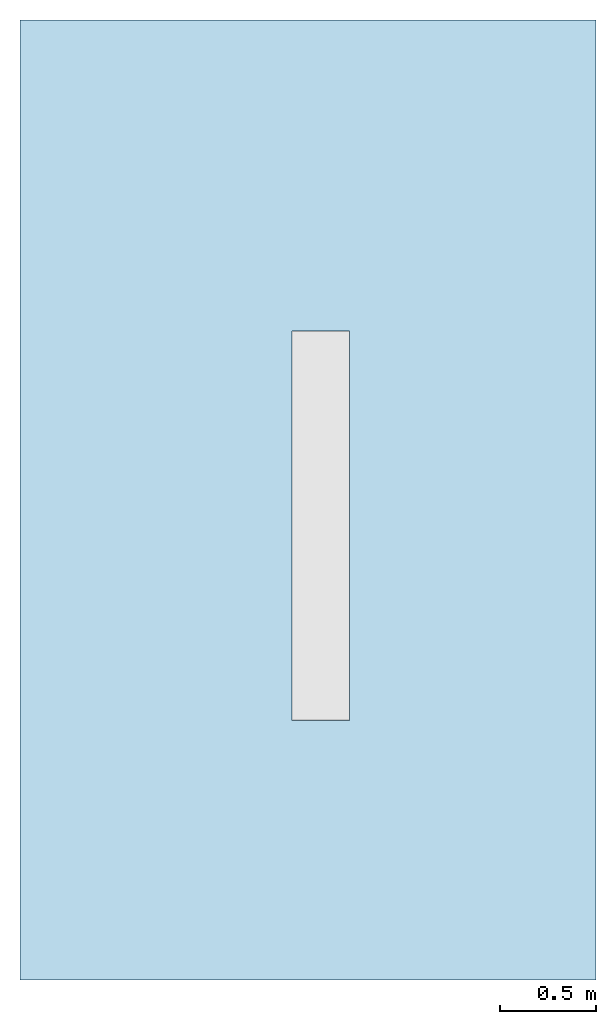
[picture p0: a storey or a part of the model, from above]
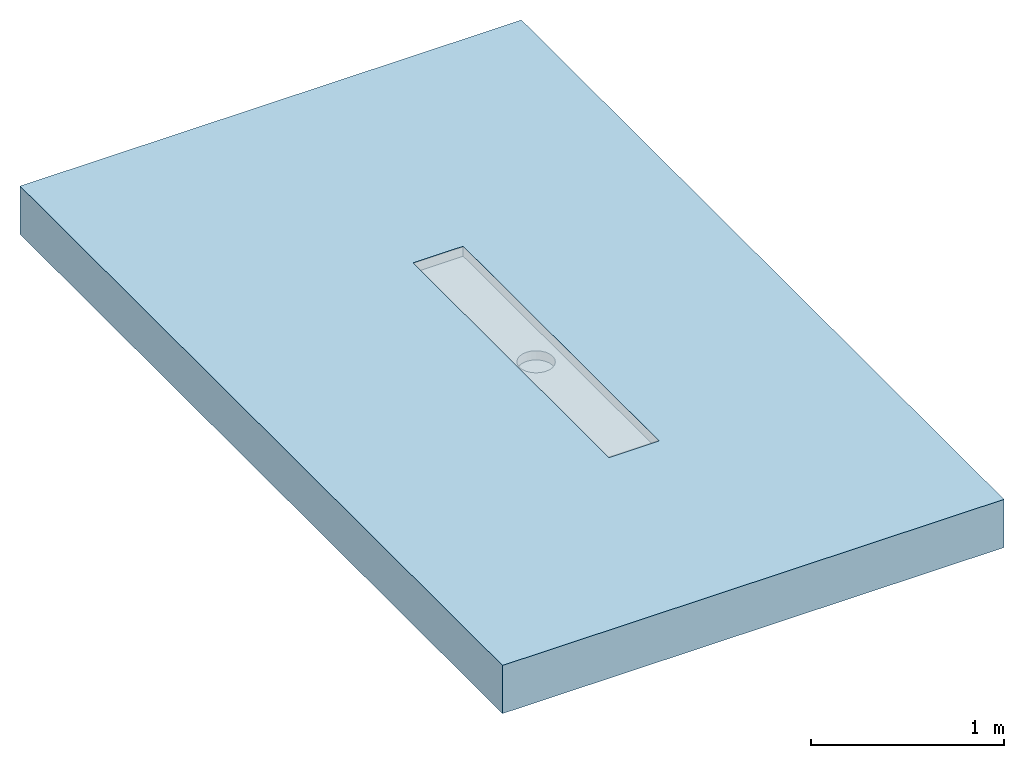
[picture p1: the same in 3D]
Properties of the parts of a building model (IFC2X3)

# File
Description: ViewDefinition [CoordinationView]
File name: Project Number
Time: 2016-11-22T11:03:20
Written by: The EXPRESS Data Manager Version 5.01.0100.02.64mod : 6 Jun 2012
Made in: 20130308_1515(x64) - Exporter 2014.0.2013.0308 - Default UI
Comment: STEP Physical File produced by: The EXPRESS Data Manager Version 5.01.0100.02.64mod : 6 Jun 2012 * Module: EDMstepFileFactory/EDMstandAlone * Creation date: Tue Nov 22 11:03:20 2016 * Host: IN-BLR-PC-0012 * Database: C:\Users\pakumar\AppData\Local\Temp\{40277E8B-09DD-453D-B419-486A75BF092F}\ifc * Database version: 5507 * Database creation date: Tue Nov 22 11:03:19 2016 * Schema: IFC2X3 * Model: DataRepository.ifc * Model creation date: Tue Nov 22 11:03:19 2016 * Header model: DataRepository.ifc_HeaderModel * Header model creation date: Tue Nov 22 11:03:19 2016 * EDMuser: sdai-user * EDMgroup: sdai-group * License ID and type: 5605 : Permanent license. Expiry date: * EDMstepFileFactory options: 020000

# IfcProject, Project Number
LongName: Project Name; Phase: Project Status

# IfcSite, Default
RefLatitude: 42, 21, 30, 344238; RefLongitude: -71, -3, -35, -194702; RefElevation: 0 mm

# IfcBuilding
Pset_BuildingCommon - NumberOfStoreys: 1
Other - Project Status: Project Status; Client Name: Owner; Project Issue Date: Issue Date; Project Address: Enter address here; Project Number: Project Number; Project Name: Project Name

# IfcBuildingStorey, Level 1
LongName: Level 1; Elevation: 0 mm
Constraints - Elevation Base: Project Base Point; Elevation: 0 mm
Graphics - Symbol at End 2 Default: yes; Symbol: Level Head - Circle: Level Head - Circle; Line Weight: 1; Line Pattern: Grid Line 1/2"; Symbol at End 1 Default: no; Color: 0
Identity Data - Name: Level 1; Building Story: yes; Structural: no
Dimensions - Computation Height: 0 mm

# IfcFlowTerminal: 416625 - Hygienic Standard Channel - with Gully 218 - 2000mm LG - 300mm Wide, ACO Tray Channel - Hygienic - Standard - 300mm Wide:416625 - Hygienic Standard Channel - with Gully 218 - 2000mm LG - 300mm Wide:634635
In: Level 1
Material: Stainless Steel AISI 304, Stainless Steel AISI 304 - Grating
Construction - Detail - Outlet 200: yes; Detail - Outlet 142mm: no; Grating: yes; 416864 - 268 x 298mm - Mesh Grating - L15 - Stainless Steel 1.4301: no; 416818 - 268 x 499mm - Ladder Grating - M125 - Stainless Steel 1.4301: no; 416812 - 268 x 298mm - Ladder Grating - R50 - Stainless Steel 1.4301: no; 416945 - 268 x 499mm - Casted Grating - M125 - Stainless Steel 1.4301: no; 416886 - 268 x 499mm - Mesh Grating - L15 - Stainless Steel 1.4301: no; 416814 - 268 x 499mm - Ladder Grating - R50 - Stainless Steel 1.4301: no; 416816 - 268 x 298mm - Ladder Grating - M125 - Stainless Steel 1.4301: no; 416884 - 268 x 298mm - Mesh Grating - L15 - Stainless Steel 1.4301: no; 416866 - 268 x 499mm - Mesh Grating - L15 - Stainless Steel 1.4301: no; 416946 - 268 x 299mm - Casted Grating - M125 - Stainless Steel 1.4301: yes
Mechanical - System Classification: Sanitary
Constraints - Level: Level: Level 1
Identity Data - Mark: 55; Website: www.acobd.com; Watermarked With: BIM Manager Premium Suite.; Watermark1: This file is the property of ACO Technologies PLC.; Watermark2: This file is water marked and users are prohibited to reproduce, adapt, distribute this information.; E-mail Sales: abdcommercial@aco.co.uk; Fax: +44 (0)1462 851490; Watermarked By: www.acobd.com; Manufacturer: ACO Building Drainage; E-mail Technical: abdtechnical@aco.co.uk; Telephone: +44 (0)1462 816666; Address: ACO Business Centre, Caxton Road, Bedford, MK41 0LF; Cost: 0
Phasing - Phase Created: New Construction
Pset_ManufacturerTypeInformation - Manufacturer: ACO Building Drainage
General - Foul air trap seal Colour: Black; Foul air trap Recycled material content: 0%; Channel Recyclable: Fully recyclable; Product Description: ACO Hygiene First Standard Kitchen Tray Channel 300 x 2030 / 200 Dia Outlet & Foul Air Trap; Maintenance guidelines: http://issuu.com/acobuildingdrainage/docs/aco_hygiene_first_catalogue/17?e=0; Channel Dimension: 300 x 2030; Foul air trap Recyclable: Fully recyclable; Product Standard: EN 1253 / EN 1672 / EN ISO 14159; Installation guidelines: http://issuu.com/acobuildingdrainage/docs/aco_hygiene_first_catalogue/17?e=0; Foul air trap seal Material: NBR; Price: POA - contact ACO; Channel Material: Stainless steel 1.4301 (EN 10088); Channel Recycled material content: 20 - 30 %; Outlet Diameter (mm): 200; Product Type: Standard Kitchen Tray Channel; Product Code: 416625; Weight (Kg): 10.7; Product Range: ACO Hygiene First; Load Class: A15 - C250 (EN 1253); Channel Colour: passivated stainless steel surface ( matt grey)
Model Properties - Grating Product Code 416866: Load Class L 15 (EN 1253) - Mesh Grate - Stainless steel 1.4301 (EN 10088) - 268 x 499 - 3.4kg; Grating Product Code 416816: N/A; Grating Product Code 416818: Load Class M 125 (EN 1253) - Ladder Grate - Stainless steel 1.4301 (EN 10088) - 268 x 499 - 6.8kg; Grating Product Code 416864: N/A; Grating Product Code 416886: Load Class L 15 (EN 1253) - Mesh Grate - Stainless steel 1.4301 (EN 10088) - 268 x 499 - 3.5kg; Grating Product Code 416945: Load Class M 125 (EN 1253) - Cast Grate - Stainless steel 1.4301 (EN 10088) - 268 x 499 - 9kg; Grating Product Code 416814: Load Class R 50 (EN 1253) - Ladder Grate - Stainless steel 1.4301 (EN 10088) - 268 x 499 - 4.2kg; Grating Product Code 416812: N/A; Grating Product Code 416946: N/A; Grating Product Code 416884: N/A
Other - Flow: 0.155385 m3/s; 416618 - Hygienic Standard Channel - 2000mm LG - 300mm Wide: yes; Number mesh: 82; 416615 - Hygienic Standard Channel - 600mm LG - 300mm Wide: no; Spigot Outlets Channels: yes; Invert Depth Detail: 51.5 mm; 416614 - Hygienic Standard Channel - 300mm LG - 300mm Wide: no; 416617 - Hygienic Standard Channel - 1500mm LG - 300mm Wide: no; 416616 - Hygienic Standard Channel - 1000mm LG - 300mm Wide: no; 416620 - Hygienic Standard Channel - 4000mm LG - 300mm Wide: no; 416619 - Hygienic Standard Channel - 3000mm LG - 300mm Wide: no
Dimensions - End Plate: 2000 mm; Number of gratings: 4; Grating Void Cut Length: 500 mm; Grating Length: 499 mm; End Connection Plate End: -2000 mm; Floor Cut Void Height: 62.8 mm; Inside Outlet Rad: 98 mm; Endplate Position: 2000 mm; Invert Depth: 50 mm; Grating Height: 21 mm; Outside Outlet Rad: 100 mm; End Connection Plate Start: -1970 mm; Depth: 29 mm; x: -2015 mm; Length Channel: -1970 mm; Outlet: 200 mm; Spigot Distance: 1000 mm

# IfcOpeningElement: Recess
In: Level 1
Phasing - Phase Created: New Construction
Dimensions - Thickness: 304.8 mm; Perimeter: 16000 mm; Volume: 160.044 ft3; Area: 161.459 ft2
Constraints - Level: Level: Level 1; Room Bounding: yes; Height Offset From Level: 0 mm; Related to Mass: no
Structural - Enable Analytical Model: no; Structural: no
Analytical Properties - Roughness: 3; Absorptance: 0.7
Identity Data - Assembly Code: B1010; Assembly Description: Floor Construction
Construction - Default Thickness: 304.8 mm; Function: Interior
Graphics - Coarse Scale Fill Color: 0

# IfcSlab: Floor:Generic - 12", Floor:Generic - 12":184145
In: Level 1
PredefinedType: FLOOR; Material: Default Floor 304.8 mm
Phasing - Phase Created: New Construction
Dimensions - Thickness: 304.8 mm; Perimeter: 16000 mm; Volume: 160.044 ft3; Area: 161.459 ft2
Constraints - Level: Level: Level 1; Room Bounding: yes; Height Offset From Level: 0 mm; Related to Mass: no
Structural - Enable Analytical Model: no; Structural: no
Pset_SlabCommon - Reference: Generic - 12"; IsExternal: no; LoadBearing: yes
Analytical Properties - Roughness: 3; Absorptance: 0.7
Identity Data - Assembly Code: B1010; Assembly Description: Floor Construction
Construction - Default Thickness: 304.8 mm; Function: Interior
Graphics - Coarse Scale Fill Color: 0
